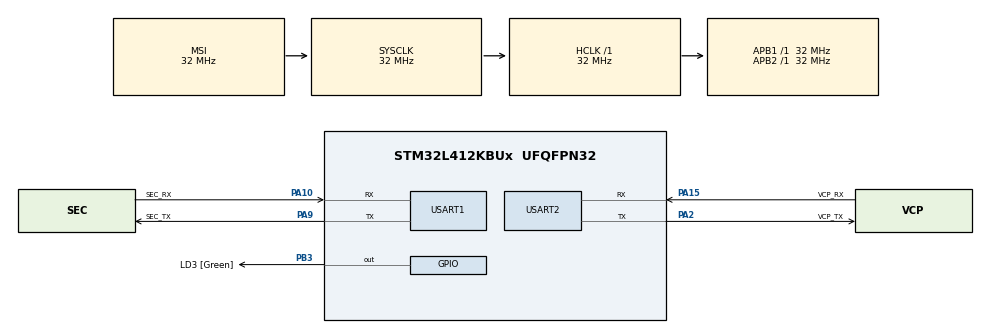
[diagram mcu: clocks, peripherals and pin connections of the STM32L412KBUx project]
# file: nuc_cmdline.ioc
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Dma.Request0=USART2_RX
Dma.Request1=USART2_TX
Dma.Request2=USART1_RX
Dma.USART1_RX.2.Direction=DMA_PERIPH_TO_MEMORY
Dma.USART1_RX.2.Instance=DMA1_Channel5
Dma.USART1_RX.2.MemDataAlignment=DMA_MDATAALIGN_BYTE
Dma.USART1_RX.2.MemInc=DMA_MINC_ENABLE
Dma.USART1_RX.2.Mode=DMA_NORMAL
Dma.USART1_RX.2.PeriphDataAlignment=DMA_PDATAALIGN_BYTE
Dma.USART1_RX.2.PeriphInc=DMA_PINC_DISABLE
Dma.USART1_RX.2.Priority=DMA_PRIORITY_LOW
Dma.USART2_RX.0.Direction=DMA_PERIPH_TO_MEMORY
Dma.USART2_RX.0.Instance=DMA1_Channel6
Dma.USART2_RX.0.MemDataAlignment=DMA_MDATAALIGN_BYTE
Dma.USART2_RX.0.MemInc=DMA_MINC_ENABLE
Dma.USART2_RX.0.Mode=DMA_NORMAL
Dma.USART2_RX.0.PeriphDataAlignment=DMA_PDATAALIGN_BYTE
Dma.USART2_RX.0.PeriphInc=DMA_PINC_DISABLE
Dma.USART2_RX.0.Priority=DMA_PRIORITY_LOW
Dma.USART2_TX.1.Direction=DMA_MEMORY_TO_PERIPH
Dma.USART2_TX.1.Instance=DMA1_Channel7
Dma.USART2_TX.1.MemDataAlignment=DMA_MDATAALIGN_BYTE
Dma.USART2_TX.1.MemInc=DMA_MINC_ENABLE
Dma.USART2_TX.1.Mode=DMA_NORMAL
Dma.USART2_TX.1.PeriphDataAlignment=DMA_PDATAALIGN_BYTE
Dma.USART2_TX.1.PeriphInc=DMA_PINC_DISABLE
Dma.USART2_TX.1.Priority=DMA_PRIORITY_LOW
Mcu.Family=STM32L4
Mcu.Name=STM32L412KBUx
Mcu.Package=UFQFPN32
NVIC.DMA1_Channel5_IRQn=true\:0\:0\:false\:false\:true\:false\:true
NVIC.DMA1_Channel6_IRQn=true\:0\:0\:false\:false\:true\:false\:true
NVIC.DMA1_Channel7_IRQn=true\:0\:0\:false\:false\:true\:false\:true
NVIC.PriorityGroup=NVIC_PRIORITYGROUP_4
NVIC.USART1_IRQn=true\:0\:0\:false\:false\:true\:true\:true
NVIC.USART2_IRQn=true\:0\:0\:false\:false\:true\:true\:true
PA0-CK_IN.Mode=HSE-External-Clock-Source-for-LittleOrca
PA0-CK_IN.Signal=RCC_CK_IN
PA10.GPIO_Label=SEC_RX
PA10.Mode=Asynchronous
PA10.Signal=USART1_RX
PA13\ (JTMS/SWDIO).GPIO_Label=SWDIO
PA13\ (JTMS/SWDIO).Mode=Serial_Wire
PA13\ (JTMS/SWDIO).Signal=SYS_JTMS-SWDIO
PA14\ (JTCK/SWCLK).GPIO_Label=SWCLK
PA14\ (JTCK/SWCLK).Mode=Serial_Wire
PA14\ (JTCK/SWCLK).Signal=SYS_JTCK-SWCLK
PA15\ (JTDI).GPIO_Label=VCP_RX
PA15\ (JTDI).Mode=Asynchronous
PA15\ (JTDI).Signal=USART2_RX
PA2.GPIO_Label=VCP_TX
PA2.Mode=Asynchronous
PA2.Signal=USART2_TX
PA9.GPIO_Label=SEC_TX
PA9.Mode=Asynchronous
PA9.Signal=USART1_TX
PB3\ (JTDO/TRACESWO).GPIO_Label=LD3 [Green]
PB3\ (JTDO/TRACESWO).Signal=GPIO_Output
PC14-OSC32_IN\ (PC14).Signal=RCC_OSC32_IN
PC15-OSC32_OUT\ (PC15).Signal=RCC_OSC32_OUT
ProjectManager.HeapSize=0x200
ProjectManager.StackSize=0x400
ProjectManager.TargetToolchain=STM32CubeIDE
RCC.ADCFreq_Value=32000000
RCC.AHBFreq_Value=32000000
RCC.APB1Freq_Value=32000000
RCC.APB1TimFreq_Value=32000000
RCC.APB2Freq_Value=32000000
RCC.APB2TimFreq_Value=32000000
RCC.CortexFreq_Value=32000000
RCC.FLatency=FLASH_LATENCY_1
RCC.HCLKFreq_Value=32000000
RCC.HSE_VALUE=8000000
RCC.HSI48_VALUE=48000000
RCC.HSICalibrationValue=16
RCC.HSI_VALUE=16000000
RCC.MSIClockRange=RCC_MSIRANGE_10
RCC.MSI_VALUE=32000000
RCC.SYSCLKFreq_VALUE=32000000
RCC.USBFreq_Value=32000000
RCC.VCOOutputFreq_Value=256000000
USART1.VirtualMode-Asynchronous=VM_ASYNC
USART2.VirtualMode-Asynchronous=VM_ASYNC
board=NUCLEO-L412KB

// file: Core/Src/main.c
/* USER CODE BEGIN Header */
/**
	******************************************************************************
	* @file           : main.c
	* @brief          : Main program body
	******************************************************************************
	* @attention
	*
	* <h2><center>&copy; Copyright (c) 2019 STMicroelectronics.
	* All rights reserved.</center></h2>
	*
	* This software component is licensed by ST under BSD 3-Clause license,
	* the "License"; You may not use this file except in compliance with the
	* License. You may obtain a copy of the License at:
	*                        opensource.org/licenses/BSD-3-Clause
	*
	******************************************************************************
	*/
/* USER CODE END Header */

#include "main.h"

/* USER CODE BEGIN Includes */
#include "board.h"
#include "app.h"
/* USER CODE END Includes */

UART_HandleTypeDef huart1;
UART_HandleTypeDef huart2;
spibus_t BOARD_SPIDEV_HANDLER;
void SystemClock_Config(void);
static void MX_GPIO_Init(void);
static void MX_DMA_Init(void);
static void MX_USART1_UART_Init(void);
static void MX_USART2_UART_Init(void);

int main(void)
{
	HAL_Init();

	SystemClock_Config();

	BOARD_SPIDEV->flags = SPI_HW_CS; // GPIO_Init depends of this

	MX_GPIO_Init();
	MX_DMA_Init();
	MX_USART1_UART_Init();
	MX_USART2_UART_Init();
	RNG_Init();

    SERIAL_Init();

	BOARD_SPIDEV->bus = SPI_BUS0;
	BOARD_SPIDEV->freq = 40000;

	SPI_Init(BOARD_SPIDEV);

	App();

	while (1)
	{
	}
}

#if 0
// 32MHz
void SystemClock_Config(void)
{
		RCC_OscInitTypeDef RCC_OscInitStruct = {0};
		RCC_ClkInitTypeDef RCC_ClkInitStruct = {0};
		RCC_PeriphCLKInitTypeDef PeriphClkInit = {0};

		/** Configure the main internal regulator output voltage
	*/
		if (HAL_PWREx_ControlVoltageScaling(PWR_REGULATOR_VOLTAGE_SCALE1) != HAL_OK)
		{
				Error_Handler();
		}
		/** Initializes the CPU, AHB and APB busses clocks
	*/
		RCC_OscInitStruct.OscillatorType = RCC_OSCILLATORTYPE_MSI;
		RCC_OscInitStruct.MSIState = RCC_MSI_ON;
		RCC_OscInitStruct.MSICalibrationValue = 0;
		RCC_OscInitStruct.MSIClockRange = RCC_MSIRANGE_10;
		RCC_OscInitStruct.PLL.PLLState = RCC_PLL_NONE;
		if (HAL_RCC_OscConfig(&RCC_OscInitStruct) != HAL_OK)
		{
				Error_Handler();
		}
		/** Initializes the CPU, AHB and APB busses clocks
	*/
		RCC_ClkInitStruct.ClockType = RCC_CLOCKTYPE_HCLK | RCC_CLOCKTYPE_SYSCLK | RCC_CLOCKTYPE_PCLK1 | RCC_CLOCKTYPE_PCLK2;
		RCC_ClkInitStruct.SYSCLKSource = RCC_SYSCLKSOURCE_MSI;
		RCC_ClkInitStruct.AHBCLKDivider = RCC_SYSCLK_DIV1;
		RCC_ClkInitStruct.APB1CLKDivider = RCC_HCLK_DIV1;
		RCC_ClkInitStruct.APB2CLKDivider = RCC_HCLK_DIV1;

		if (HAL_RCC_ClockConfig(&RCC_ClkInitStruct, FLASH_LATENCY_1) != HAL_OK)
		{
				Error_Handler();
		}
		PeriphClkInit.PeriphClockSelection = RCC_PERIPHCLK_USART1 | RCC_PERIPHCLK_USART2;
		PeriphClkInit.Usart1ClockSelection = RCC_USART1CLKSOURCE_PCLK2;
		PeriphClkInit.Usart2ClockSelection = RCC_USART2CLKSOURCE_PCLK1;
		if (HAL_RCCEx_PeriphCLKConfig(&PeriphClkInit) != HAL_OK)
		{
				Error_Handler();
		}
}
#else
//80 MHz
void SystemClock_Config(void)
{
		RCC_OscInitTypeDef RCC_OscInitStruct = {0};
		RCC_ClkInitTypeDef RCC_ClkInitStruct = {0};
		RCC_PeriphCLKInitTypeDef PeriphClkInit = {0};

		/** Configure the main internal regulator output voltage
	*/
		if (HAL_PWREx_ControlVoltageScaling(PWR_REGULATOR_VOLTAGE_SCALE1) != HAL_OK)
		{
				Error_Handler();
		}
		/** Initializes the CPU, AHB and APB busses clocks
	*/
		RCC_OscInitStruct.OscillatorType = RCC_OSCILLATORTYPE_MSI;
		RCC_OscInitStruct.MSIState = RCC_MSI_ON;
		RCC_OscInitStruct.MSICalibrationValue = 0;
		RCC_OscInitStruct.MSIClockRange = RCC_MSIRANGE_6;
		RCC_OscInitStruct.PLL.PLLState = RCC_PLL_ON;
		RCC_OscInitStruct.PLL.PLLSource = RCC_PLLSOURCE_MSI;
		RCC_OscInitStruct.PLL.PLLM = 1;
		RCC_OscInitStruct.PLL.PLLN = 40;
		RCC_OscInitStruct.PLL.PLLQ = RCC_PLLQ_DIV2;
		RCC_OscInitStruct.PLL.PLLR = RCC_PLLR_DIV2;
		if (HAL_RCC_OscConfig(&RCC_OscInitStruct) != HAL_OK)
		{
				Error_Handler();
		}
		/** Initializes the CPU, AHB and APB busses clocks
	*/
		RCC_ClkInitStruct.ClockType = RCC_CLOCKTYPE_HCLK | RCC_CLOCKTYPE_SYSCLK | RCC_CLOCKTYPE_PCLK1 | RCC_CLOCKTYPE_PCLK2;
		RCC_ClkInitStruct.SYSCLKSource = RCC_SYSCLKSOURCE_PLLCLK;
		RCC_ClkInitStruct.AHBCLKDivider = RCC_SYSCLK_DIV1;
		RCC_ClkInitStruct.APB1CLKDivider = RCC_HCLK_DIV1;
		RCC_ClkInitStruct.APB2CLKDivider = RCC_HCLK_DIV1;

		if (HAL_RCC_ClockConfig(&RCC_ClkInitStruct, FLASH_LATENCY_4) != HAL_OK)
		{
				Error_Handler();
		}
		PeriphClkInit.PeriphClockSelection = RCC_PERIPHCLK_USART2;
		PeriphClkInit.Usart2ClockSelection = RCC_USART2CLKSOURCE_PCLK1;
		if (HAL_RCCEx_PeriphCLKConfig(&PeriphClkInit) != HAL_OK)
		{
				Error_Handler();
		}
}
#endif

static void MX_USART1_UART_Init(void)
{

		huart1.Instance = USART1;
		huart1.Init.BaudRate = 115200;
		huart1.Init.WordLength = UART_WORDLENGTH_8B;
		huart1.Init.StopBits = UART_STOPBITS_1;
		huart1.Init.Parity = UART_PARITY_NONE;
		huart1.Init.Mode = UART_MODE_TX_RX;
		huart1.Init.HwFlowCtl = UART_HWCONTROL_NONE;
		huart1.Init.OverSampling = UART_OVERSAMPLING_16;
		huart1.Init.OneBitSampling = UART_ONE_BIT_SAMPLE_DISABLE;
		huart1.AdvancedInit.AdvFeatureInit = UART_ADVFEATURE_NO_INIT;
		if (HAL_UART_Init(&huart1) != HAL_OK)
		{
				Error_Handler();
		}
}

static void MX_USART2_UART_Init(void)
{

		huart2.Instance = USART2;
		huart2.Init.BaudRate = 115200;
		huart2.Init.WordLength = UART_WORDLENGTH_8B;
		huart2.Init.StopBits = UART_STOPBITS_1;
		huart2.Init.Parity = UART_PARITY_NONE;
		huart2.Init.Mode = UART_MODE_TX_RX;
		huart2.Init.HwFlowCtl = UART_HWCONTROL_NONE;
		huart2.Init.OverSampling = UART_OVERSAMPLING_16;
		huart2.Init.OneBitSampling = UART_ONE_BIT_SAMPLE_DISABLE;
		huart2.AdvancedInit.AdvFeatureInit = UART_ADVFEATURE_NO_INIT;
		if (HAL_UART_Init(&huart2) != HAL_OK)
		{
				Error_Handler();
		}
}

static void MX_DMA_Init(void)
{
		/* DMA controller clock enable */
		__HAL_RCC_DMA1_CLK_ENABLE();
		__HAL_RCC_DMA2_CLK_ENABLE();
}

static void MX_GPIO_Init(void)
{
		GPIO_InitTypeDef GPIO_InitStruct = {0};

		/* GPIO Ports Clock Enable */
		__HAL_RCC_GPIOC_CLK_ENABLE();
		__HAL_RCC_GPIOA_CLK_ENABLE();
		__HAL_RCC_GPIOB_CLK_ENABLE();

		/*Configure GPIO pin Output Level */
		HAL_GPIO_WritePin(LD3_GPIO_Port, LD3_Pin, GPIO_PIN_RESET);

		/*Configure GPIO pin : LD3_Pin */
		GPIO_InitStruct.Pin = LD3_Pin;
		GPIO_InitStruct.Mode = GPIO_MODE_OUTPUT_PP;
		GPIO_InitStruct.Pull = GPIO_NOPULL;
		GPIO_InitStruct.Speed = GPIO_SPEED_FREQ_HIGH;
		HAL_GPIO_Init(LD3_GPIO_Port, &GPIO_InitStruct);

		if(BOARD_SPIDEV->flags & SPI_HW_CS){
			GPIO_InitStruct.Pin = LCD_CK_Pin | LCD_DI_Pin | LCD_CS_Pin;
		}else{
			GPIO_InitStruct.Pin = LCD_CK_Pin | LCD_DI_Pin;
		}
		GPIO_InitStruct.Mode = GPIO_MODE_AF_PP;
		GPIO_InitStruct.Pull = GPIO_NOPULL;
		GPIO_InitStruct.Speed = GPIO_SPEED_FREQ_VERY_HIGH;
		GPIO_InitStruct.Alternate = GPIO_AF5_SPI1;
		HAL_GPIO_Init(GPIOA, &GPIO_InitStruct);

		/*Configure GPIO pins : LCD_BKL_Pin LCD_CS_Pin LCD_CD_Pin */
		GPIO_InitStruct.Mode = GPIO_MODE_OUTPUT_PP;
		GPIO_InitStruct.Pull = GPIO_NOPULL;
		GPIO_InitStruct.Speed = GPIO_SPEED_FREQ_LOW;

		if(!(BOARD_SPIDEV->flags & SPI_HW_CS)){
			GPIO_InitStruct.Pin = LCD_CS_Pin;
			HAL_GPIO_Init(LCD_CS_GPIO_Port, &GPIO_InitStruct);
		}

		GPIO_InitStruct.Pin = LCD_CD_Pin;
		HAL_GPIO_Init(LCD_CD_GPIO_Port, &GPIO_InitStruct);

		GPIO_InitStruct.Pin = LCD_BKL_Pin;
		HAL_GPIO_Init(LCD_BKL_GPIO_Port, &GPIO_InitStruct);
}

void Error_Handler(void)
{
		__disable_irq();
		while (1)
		{
		}
}

void __debugbreak(void){
	__asm volatile(
        "bkpt #01 \n"
        "b . \n"
    );
}

void Fault_Handler(void)
{
    volatile uint8_t isr_number = (SCB->ICSR & 255) - 16;
    // See position number on Table 46 from RM0394
    UNUSED(isr_number);

    __asm volatile(
        "bkpt #01 \n"
        "b . \n"
    );
}

typedef struct {
    uint32_t r0;
    uint32_t r1;
    uint32_t r2;
    uint32_t r3;
    uint32_t r12;
    uint32_t lr;
    uint32_t pc;
    uint32_t psr;
}stackframe_t;

void Stack_Dump(stackframe_t *stack){
    //GPIOJ->MODER = (1 << 26);
    //HAL_GPIO_WritePin(GPIOJ, GPIO_PIN_13, GPIO_PIN_SET);

    __asm volatile(
        "bkpt #01 \n"
        "b . \n"
    );
}

/************************ (C) COPYRIGHT STMicroelectronics *****END OF FILE****/
